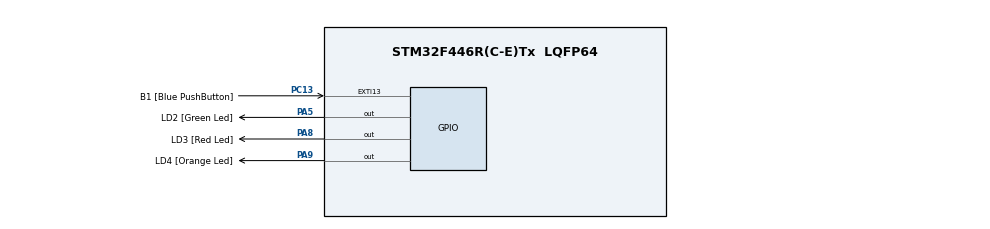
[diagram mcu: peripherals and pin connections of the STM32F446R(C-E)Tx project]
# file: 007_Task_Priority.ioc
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Mcu.Family=STM32F4
Mcu.Name=STM32F446R(C-E)Tx
Mcu.Package=LQFP64
NVIC.EXTI15_10_IRQn=true\:6\:0\:true\:false\:true\:true\:true\:true
NVIC.PriorityGroup=NVIC_PRIORITYGROUP_4
NVIC.TIM5_IRQn=true\:15\:0\:false\:false\:true\:false\:true\:true
NVIC.TimeBase=TIM5_IRQn
NVIC.TimeBaseIP=TIM5
PA13.GPIO_Label=TMS
PA13.Signal=SYS_JTMS-SWDIO
PA14.GPIO_Label=TCK
PA14.Signal=SYS_JTCK-SWCLK
PA2.GPIO_Label=USART_TX
PA2.Signal=USART2_TX
PA3.GPIO_Label=USART_RX
PA3.Signal=USART2_RX
PA5.GPIO_Label=LD2 [Green Led]
PA5.Signal=GPIO_Output
PA8.GPIO_Label=LD3 [Red Led]
PA8.Signal=GPIO_Output
PA9.GPIO_Label=LD4 [Orange Led]
PA9.Signal=GPIO_Output
PB3.GPIO_Label=SWO
PB3.Signal=SYS_JTDO-SWO
PC13.GPIO_Label=B1 [Blue PushButton]
PC13.GPIO_ModeDefaultEXTI=GPIO_MODE_IT_FALLING
PC13.Signal=GPXTI13
PC14-OSC32_IN.Signal=RCC_OSC32_IN
PC15-OSC32_OUT.Signal=RCC_OSC32_OUT
PH0-OSC_IN.Signal=RCC_OSC_IN
PH1-OSC_OUT.Signal=RCC_OSC_OUT
ProjectManager.HeapSize=0x200
ProjectManager.StackSize=0x400
ProjectManager.TargetToolchain=STM32CubeIDE
RCC.AHBFreq_Value=84000000
RCC.APB1CLKDivider=RCC_HCLK_DIV2
RCC.APB1Freq_Value=42000000
RCC.APB1TimFreq_Value=84000000
RCC.APB2Freq_Value=84000000
RCC.APB2TimFreq_Value=84000000
RCC.CortexFreq_Value=84000000
RCC.FLatency-AdvancedSettings=FLASH_LATENCY_2
RCC.HCLKFreq_Value=84000000
RCC.HSE_VALUE=8000000
RCC.HSI_VALUE=16000000
RCC.LSE_VALUE=32768
RCC.PLLN=336
RCC.PLLP=RCC_PLLP_DIV4
RCC.SYSCLKFreq_VALUE=84000000
RCC.SYSCLKSource=RCC_SYSCLKSOURCE_PLLCLK
RCC.USBFreq_Value=168000000
RCC.VCOOutputFreq_Value=336000000
VP_SYS_VS_tim5.Mode=TIM5
board=NUCLEO-F446RE

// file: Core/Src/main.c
/* USER CODE BEGIN Header */
/**
  ******************************************************************************
  * @file           : main.c
  * @brief          : Main program body
  ******************************************************************************
  * @attention
  *
  * Copyright (c) 2023 STMicroelectronics.
  * All rights reserved.
  *
  * This software is licensed under terms that can be found in the LICENSE file
  * in the root directory of this software component.
  * If no LICENSE file comes with this software, it is provided AS-IS.
  *
  ******************************************************************************
  */
/* USER CODE END Header */
#include "main.h"

/* USER CODE BEGIN Includes */

#include "FreeRTOS.h"
#include "task.h"

/* USER CODE END Includes */

/* USER CODE BEGIN PD */

#define DWT_CTRL    (*(volatile uint32_t*)0xE0001000)

/* USER CODE END PD */

/* USER CODE BEGIN PV */

volatile BaseType_t switch_priority_flag = 0;

/* USER CODE END PV */

void SystemClock_Config(void);
static void MX_GPIO_Init(void);
/* USER CODE BEGIN PFP */

static void task1_handler(void* parameters);
static void task2_handler(void* parameters);

extern void SEGGER_UART_init(uint32_t);

TaskHandle_t task1_handle;
TaskHandle_t task2_handle;

/* USER CODE END PFP */

int main(void)
{
  /* USER CODE BEGIN 1 */

	BaseType_t status;

  /* USER CODE END 1 */

  /* MCU Configuration--------------------------------------------------------*/

  /* Reset of all peripherals, Initializes the Flash interface and the Systick. */
  HAL_Init();

  /* Configure the system clock */
  SystemClock_Config();

  /* Initialize all configured peripherals */
  MX_GPIO_Init();
  /* USER CODE BEGIN 2 */

  SEGGER_UART_init(500000);

  // CYCLCNT enable
  DWT_CTRL |= (1<<0);

  SEGGER_SYSVIEW_Conf();

  status = xTaskCreate(task1_handler, "Task1", 200, NULL, 2, &task1_handle);

  configASSERT(status == pdPASS);

  status = xTaskCreate(task2_handler, "Task2", 200, NULL, 1, &task2_handle);

  configASSERT(status == pdPASS);

  // Start the freeRTOS scheduler
  vTaskStartScheduler();

  /* USER CODE END 2 */

  /* Infinite loop */
  while (1)
  {

  }
}

void SystemClock_Config(void)
{
  RCC_OscInitTypeDef RCC_OscInitStruct = {0};
  RCC_ClkInitTypeDef RCC_ClkInitStruct = {0};

  /** Configure the main internal regulator output voltage
  */
  __HAL_RCC_PWR_CLK_ENABLE();
  __HAL_PWR_VOLTAGESCALING_CONFIG(PWR_REGULATOR_VOLTAGE_SCALE1);

  /** Initializes the RCC Oscillators according to the specified parameters
  * in the RCC_OscInitTypeDef structure.
  */
  RCC_OscInitStruct.OscillatorType = RCC_OSCILLATORTYPE_HSI;
  RCC_OscInitStruct.HSIState = RCC_HSI_ON;
  RCC_OscInitStruct.HSICalibrationValue = RCC_HSICALIBRATION_DEFAULT;
  RCC_OscInitStruct.PLL.PLLState = RCC_PLL_ON;
  RCC_OscInitStruct.PLL.PLLSource = RCC_PLLSOURCE_HSI;
  RCC_OscInitStruct.PLL.PLLM = 8;
  RCC_OscInitStruct.PLL.PLLN = 168;
  RCC_OscInitStruct.PLL.PLLP = RCC_PLLP_DIV2;
  RCC_OscInitStruct.PLL.PLLQ = 2;
  RCC_OscInitStruct.PLL.PLLR = 2;
  if (HAL_RCC_OscConfig(&RCC_OscInitStruct) != HAL_OK)
  {
    Error_Handler();
  }

  /** Initializes the CPU, AHB and APB buses clocks
  */
  RCC_ClkInitStruct.ClockType = RCC_CLOCKTYPE_HCLK|RCC_CLOCKTYPE_SYSCLK
                              |RCC_CLOCKTYPE_PCLK1|RCC_CLOCKTYPE_PCLK2;
  RCC_ClkInitStruct.SYSCLKSource = RCC_SYSCLKSOURCE_PLLCLK;
  RCC_ClkInitStruct.AHBCLKDivider = RCC_SYSCLK_DIV1;
  RCC_ClkInitStruct.APB1CLKDivider = RCC_HCLK_DIV4;
  RCC_ClkInitStruct.APB2CLKDivider = RCC_HCLK_DIV2;

  if (HAL_RCC_ClockConfig(&RCC_ClkInitStruct, FLASH_LATENCY_5) != HAL_OK)
  {
    Error_Handler();
  }
}

static void MX_GPIO_Init(void)
{
  GPIO_InitTypeDef GPIO_InitStruct = {0};

  /* GPIO Ports Clock Enable */
  __HAL_RCC_GPIOC_CLK_ENABLE();
  __HAL_RCC_GPIOH_CLK_ENABLE();
  __HAL_RCC_GPIOA_CLK_ENABLE();
  __HAL_RCC_GPIOB_CLK_ENABLE();

  /*Configure GPIO pin Output Level */
  HAL_GPIO_WritePin(GPIOA, LD2_Pin|LD3_Pin|LD4_Pin, GPIO_PIN_RESET);

  /*Configure GPIO pin : B1_Pin */
  GPIO_InitStruct.Pin = B1_Pin;
  GPIO_InitStruct.Mode = GPIO_MODE_IT_FALLING;
  GPIO_InitStruct.Pull = GPIO_NOPULL;
  HAL_GPIO_Init(B1_GPIO_Port, &GPIO_InitStruct);

  /*Configure GPIO pins : USART_TX_Pin USART_RX_Pin */
  GPIO_InitStruct.Pin = USART_TX_Pin|USART_RX_Pin;
  GPIO_InitStruct.Mode = GPIO_MODE_AF_PP;
  GPIO_InitStruct.Pull = GPIO_NOPULL;
  GPIO_InitStruct.Speed = GPIO_SPEED_FREQ_VERY_HIGH;
  GPIO_InitStruct.Alternate = GPIO_AF7_USART2;
  HAL_GPIO_Init(GPIOA, &GPIO_InitStruct);

  /*Configure GPIO pins : LD2_Pin LD3_Pin LD4_Pin */
  GPIO_InitStruct.Pin = LD2_Pin|LD3_Pin|LD4_Pin;
  GPIO_InitStruct.Mode = GPIO_MODE_OUTPUT_PP;
  GPIO_InitStruct.Pull = GPIO_NOPULL;
  GPIO_InitStruct.Speed = GPIO_SPEED_FREQ_LOW;
  HAL_GPIO_Init(GPIOA, &GPIO_InitStruct);

  /* EXTI interrupt init*/
  HAL_NVIC_SetPriority(EXTI15_10_IRQn, 6, 0);
  HAL_NVIC_EnableIRQ(EXTI15_10_IRQn);

}

/* USER CODE BEGIN 4 */

void button_interrupt_handler(void){

	traceISR_ENTER();
	switch_priority_flag = 1;
	traceISR_EXIT();

}

void switch_priority(void){

	portENTER_CRITICAL();
	if(switch_priority_flag == 1){
		UBaseType_t tempPriority = uxTaskPriorityGet(task1_handle);
		vTaskPrioritySet(task1_handle, uxTaskPriorityGet(task2_handle));
		vTaskPrioritySet(task2_handle, tempPriority);
		switch_priority_flag = 0;
	}
	portEXIT_CRITICAL();

}

static void task1_handler(void* parameters){

	while(1){
		SEGGER_SYSVIEW_PrintfTarget("Toggling Task1 LED");
		HAL_GPIO_TogglePin(GPIOA, TASK1_PIN);
		HAL_Delay(100);
		switch_priority();
	}
}

static void task2_handler(void* parameters){

	while(1){
		SEGGER_SYSVIEW_PrintfTarget("Toggling Task2 LED");
		HAL_GPIO_TogglePin(GPIOA, TASK2_PIN);
		HAL_Delay(1000);
		switch_priority();
	}
}

/* USER CODE END 4 */

void HAL_TIM_PeriodElapsedCallback(TIM_HandleTypeDef *htim)
{
  if (htim->Instance == TIM5) {
    HAL_IncTick();
  }
}

void Error_Handler(void)
{
  __disable_irq();
  while (1)
  {
  }
}
